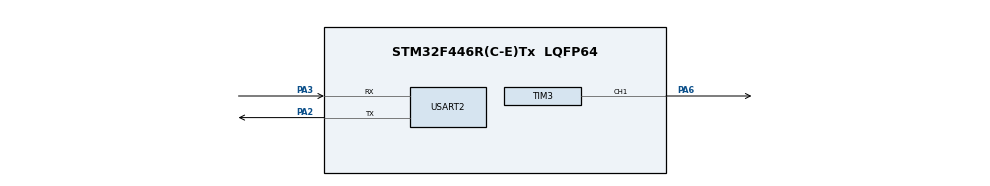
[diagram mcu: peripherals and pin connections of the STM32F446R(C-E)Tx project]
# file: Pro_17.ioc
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Mcu.Family=STM32F4
Mcu.Name=STM32F446R(C-E)Tx
Mcu.Package=LQFP64
NVIC.PriorityGroup=NVIC_PRIORITYGROUP_4
NVIC.USART2_IRQn=true\:0\:0\:false\:false\:true\:true\:true\:true
PA2.Mode=Asynchronous
PA2.Signal=USART2_TX
PA3.Mode=Asynchronous
PA3.Signal=USART2_RX
PA6.Signal=S_TIM3_CH1
ProjectManager.HeapSize=0x200
ProjectManager.StackSize=0x400
ProjectManager.TargetToolchain=STM32CubeIDE
RCC.CortexFreq_Value=16000000
RCC.USBFreq_Value=96000000
RCC.VCOOutputFreq_Value=192000000
SH.S_TIM3_CH1.0=TIM3_CH1,PWM Generation1 CH1
TIM3.Channel-PWM\ Generation1\ CH1=TIM_CHANNEL_1
TIM3.Period=19999
TIM3.Prescaler=89
TIM3.Pulse-PWM\ Generation1\ CH1=1000
USART2.VirtualMode=VM_ASYNC
board=custom

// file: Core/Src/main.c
/* USER CODE BEGIN Header */
/**
  ******************************************************************************
  * @file           : main.c
  * @brief          : Main program body
  ******************************************************************************
  * @attention
  *
  * Copyright (c) 2026 STMicroelectronics.
  * All rights reserved.
  *
  * This software is licensed under terms that can be found in the LICENSE file
  * in the root directory of this software component.
  * If no LICENSE file comes with this software, it is provided AS-IS.
  *
  ******************************************************************************
  */
/* USER CODE END Header */
#include "main.h"

/* USER CODE BEGIN Includes */

#include <string.h>
#include <stdlib.h>
#include <stdio.h>

/* USER CODE END Includes */

TIM_HandleTypeDef htim3;

UART_HandleTypeDef huart2;

/* USER CODE BEGIN PV */

uint8_t rxByte;
char rxBuffer[20];
uint8_t rxIndex = 0;
volatile uint8_t lineReady = 0;

/* USER CODE END PV */

void SystemClock_Config(void);
static void MX_GPIO_Init(void);
static void MX_TIM3_Init(void);
static void MX_USART2_UART_Init(void);

int main(void)
{

  /* MCU Configuration--------------------------------------------------------*/

  /* Reset of all peripherals, Initializes the Flash interface and the Systick. */
  HAL_Init();

  /* Configure the system clock */
  SystemClock_Config();

  /* Initialize all configured peripherals */
  MX_GPIO_Init();
  MX_TIM3_Init();
  MX_USART2_UART_Init();
  /* USER CODE BEGIN 2 */

  HAL_TIM_PWM_Start(&htim3, TIM_CHANNEL_1);

  /* Start UART interrupt reception */
  HAL_UART_Receive_IT(&huart2, &rxByte, 1);

  /* Start servo at 90 degrees */
  __HAL_TIM_SET_COMPARE(&htim3, TIM_CHANNEL_1, 1500);

  /* USER CODE END 2 */

  /* Initialize leds */
  BSP_LED_Init(LED2);

  /* Initialize USER push-button, will be used to trigger an interrupt each time it's pressed.*/
  BSP_PB_Init(BUTTON_USER, BUTTON_MODE_EXTI);

  /* Infinite loop */
  /* USER CODE BEGIN WHILE */
  /* USER CODE BEGIN WHILE */

  while (1)
  {
      if (lineReady)
      {
          int angle = atoi(rxBuffer);

          if (angle >= 0 && angle <= 180)
          {
              uint16_t pulse_us;

              /* Convert angle to servo pulse width */
              pulse_us = 1000 + ((angle * 1000) / 180);

              /* Move servo to requested angle */
              __HAL_TIM_SET_COMPARE(&htim3, TIM_CHANNEL_1, pulse_us);

              char msg[50];

              sprintf(msg, "Moved to %d deg\r\n", angle);

              HAL_UART_Transmit(
                  &huart2,
                  (uint8_t *)msg,
                  strlen(msg),
                  HAL_MAX_DELAY
              );

              /* Give servo time to reach the position */
              HAL_Delay(2000);

              /* Return servo to 0 degrees */
              __HAL_TIM_SET_COMPARE(&htim3, TIM_CHANNEL_1, 1000);

              HAL_Delay(1000);

              /* Tell user that servo is ready again */
              char readyMsg[] = "Motor ready for rotation again\r\n";

              HAL_UART_Transmit(
                  &huart2,
                  (uint8_t *)readyMsg,
                  strlen(readyMsg),
                  HAL_MAX_DELAY
              );
          }
          else
          {
              char msg[] = "Invalid angle! Use 0-180\r\n";

              HAL_UART_Transmit(
                  &huart2,
                  (uint8_t *)msg,
                  strlen(msg),
                  HAL_MAX_DELAY
              );
          }

          /* Clear buffer */
          rxIndex = 0;
          memset(rxBuffer, 0, sizeof(rxBuffer));
          lineReady = 0;
      }
  }

  /* USER CODE END WHILE */
  /* USER CODE END 3 */
}

void SystemClock_Config(void)
{
  RCC_OscInitTypeDef RCC_OscInitStruct = {0};
  RCC_ClkInitTypeDef RCC_ClkInitStruct = {0};

  /** Configure the main internal regulator output voltage
  */
  __HAL_RCC_PWR_CLK_ENABLE();
  __HAL_PWR_VOLTAGESCALING_CONFIG(PWR_REGULATOR_VOLTAGE_SCALE3);

  /** Initializes the RCC Oscillators according to the specified parameters
  * in the RCC_OscInitTypeDef structure.
  */
  RCC_OscInitStruct.OscillatorType = RCC_OSCILLATORTYPE_HSI;
  RCC_OscInitStruct.HSIState = RCC_HSI_ON;
  RCC_OscInitStruct.HSICalibrationValue = RCC_HSICALIBRATION_DEFAULT;
  RCC_OscInitStruct.PLL.PLLState = RCC_PLL_ON;
  RCC_OscInitStruct.PLL.PLLSource = RCC_PLLSOURCE_HSI;
  RCC_OscInitStruct.PLL.PLLM = 16;
  RCC_OscInitStruct.PLL.PLLN = 336;
  RCC_OscInitStruct.PLL.PLLP = RCC_PLLP_DIV4;
  RCC_OscInitStruct.PLL.PLLQ = 2;
  RCC_OscInitStruct.PLL.PLLR = 2;
  if (HAL_RCC_OscConfig(&RCC_OscInitStruct) != HAL_OK)
  {
    Error_Handler();
  }

  /** Initializes the CPU, AHB and APB buses clocks
  */
  RCC_ClkInitStruct.ClockType = RCC_CLOCKTYPE_HCLK|RCC_CLOCKTYPE_SYSCLK
                              |RCC_CLOCKTYPE_PCLK1|RCC_CLOCKTYPE_PCLK2;
  RCC_ClkInitStruct.SYSCLKSource = RCC_SYSCLKSOURCE_PLLCLK;
  RCC_ClkInitStruct.AHBCLKDivider = RCC_SYSCLK_DIV1;
  RCC_ClkInitStruct.APB1CLKDivider = RCC_HCLK_DIV2;
  RCC_ClkInitStruct.APB2CLKDivider = RCC_HCLK_DIV1;

  if (HAL_RCC_ClockConfig(&RCC_ClkInitStruct, FLASH_LATENCY_2) != HAL_OK)
  {
    Error_Handler();
  }
}

static void MX_TIM3_Init(void)
{

  TIM_ClockConfigTypeDef sClockSourceConfig = {0};
  TIM_MasterConfigTypeDef sMasterConfig = {0};
  TIM_OC_InitTypeDef sConfigOC = {0};

  htim3.Instance = TIM3;
  htim3.Init.Prescaler = 83;
  htim3.Init.CounterMode = TIM_COUNTERMODE_UP;
  htim3.Init.Period = 19999;
  htim3.Init.ClockDivision = TIM_CLOCKDIVISION_DIV1;
  htim3.Init.AutoReloadPreload = TIM_AUTORELOAD_PRELOAD_DISABLE;
  if (HAL_TIM_Base_Init(&htim3) != HAL_OK)
  {
    Error_Handler();
  }
  sClockSourceConfig.ClockSource = TIM_CLOCKSOURCE_INTERNAL;
  if (HAL_TIM_ConfigClockSource(&htim3, &sClockSourceConfig) != HAL_OK)
  {
    Error_Handler();
  }
  if (HAL_TIM_PWM_Init(&htim3) != HAL_OK)
  {
    Error_Handler();
  }
  sMasterConfig.MasterOutputTrigger = TIM_TRGO_RESET;
  sMasterConfig.MasterSlaveMode = TIM_MASTERSLAVEMODE_DISABLE;
  if (HAL_TIMEx_MasterConfigSynchronization(&htim3, &sMasterConfig) != HAL_OK)
  {
    Error_Handler();
  }
  sConfigOC.OCMode = TIM_OCMODE_PWM1;
  sConfigOC.Pulse = 0;
  sConfigOC.OCPolarity = TIM_OCPOLARITY_HIGH;
  sConfigOC.OCFastMode = TIM_OCFAST_DISABLE;
  if (HAL_TIM_PWM_ConfigChannel(&htim3, &sConfigOC, TIM_CHANNEL_1) != HAL_OK)
  {
    Error_Handler();
  }
  HAL_TIM_MspPostInit(&htim3);

}

static void MX_USART2_UART_Init(void)
{

  huart2.Instance = USART2;
  huart2.Init.BaudRate = 115200;
  huart2.Init.WordLength = UART_WORDLENGTH_8B;
  huart2.Init.StopBits = UART_STOPBITS_1;
  huart2.Init.Parity = UART_PARITY_NONE;
  huart2.Init.Mode = UART_MODE_TX_RX;
  huart2.Init.HwFlowCtl = UART_HWCONTROL_NONE;
  huart2.Init.OverSampling = UART_OVERSAMPLING_16;
  if (HAL_UART_Init(&huart2) != HAL_OK)
  {
    Error_Handler();
  }

}

static void MX_GPIO_Init(void)
{

  /* GPIO Ports Clock Enable */
  __HAL_RCC_GPIOC_CLK_ENABLE();
  __HAL_RCC_GPIOH_CLK_ENABLE();
  __HAL_RCC_GPIOA_CLK_ENABLE();
  __HAL_RCC_GPIOB_CLK_ENABLE();

}

/* USER CODE BEGIN 4 */

void HAL_UART_RxCpltCallback(UART_HandleTypeDef *huart)
{
    if (huart->Instance == USART2)
    {
        if (rxByte == '\r' || rxByte == '\n')
        {
            if (rxIndex > 0)
            {
                rxBuffer[rxIndex] = '\0';
                lineReady = 1;
            }
        }
        else
        {
            if (rxIndex < sizeof(rxBuffer) - 1)
            {
                rxBuffer[rxIndex++] = rxByte;
            }
        }

        HAL_UART_Receive_IT(&huart2, &rxByte, 1);
    }
}

/* USER CODE END 4 */

void Error_Handler(void)
{
  __disable_irq();
  while (1)
  {
  }
}
